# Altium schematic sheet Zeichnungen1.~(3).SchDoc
size A4

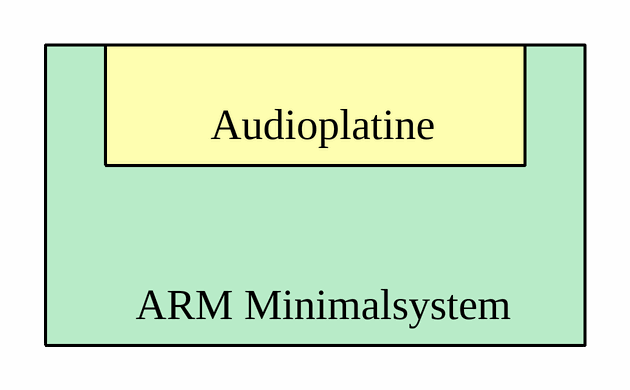
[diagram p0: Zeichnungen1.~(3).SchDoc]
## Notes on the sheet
- Audioplatine
- ARM Minimalsystem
